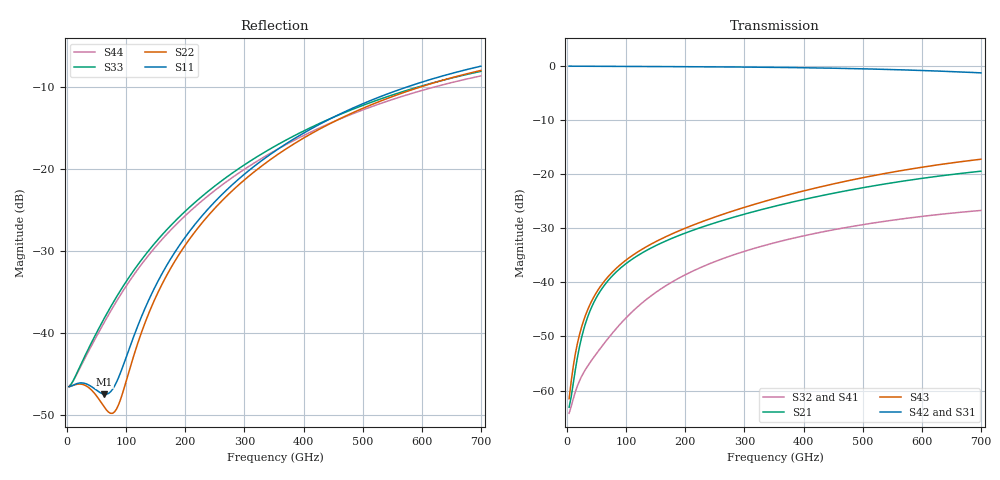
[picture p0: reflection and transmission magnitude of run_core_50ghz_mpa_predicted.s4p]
#  Hz  S  RI  R  50
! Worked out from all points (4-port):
!   200 points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, 3.5 GHz to 700 GHz, reference 50 ohm
!   strongest paths, dB at 3.5 GHz, 178.5 GHz, 353.5 GHz, 528.5 GHz, 700 GHz:
!     S42: 0.0, -0.1, -0.3, -0.6, -1.3
!     S31: 0.0, -0.1, -0.3, -0.6, -1.3
!     S43: -61.5, -31.0, -24.4, -20.1, -17.2
!     S21: -63.1, -31.8, -25.9, -22.0, -19.5
!     S32: -64.2, -39.9, -32.6, -28.9, -26.7
!     S41: -64.2, -40.0, -32.7, -28.9, -26.7
!   lowest |S11| = -47.5 dB at 63 GHz (marker M1), VSWR 1.01, Z = 50.2 - j0.359 ohm
!   |S11| at or under -10 dB: start of sweep to 576.9 GHz
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3.5e9  0.00468 -1.39e-05  0.000623 0.000322  0.9948 -0.00852  -0.000566 0.000226
       0.000623 0.000323  0.00469 2.23e-05  -0.000568 0.000223  0.9948 -0.00847
       0.9948 -0.00843  -0.00056 0.000256  0.0047 7.81e-05  0.000669 0.000508
       -0.000561 0.000253  0.9947 -0.00842  0.000668 0.00051  0.0047 0.000144
2.45e10  0.00488 -0.000778  0.000272 0.00306  0.9915 -0.0582  -0.000142 0.00115
         0.000275 0.00306  0.00483 -0.000397  -0.000147 0.00113  0.9916 -0.058
         0.9917 -0.0577  -0.000109 0.00134  0.00651 -0.000523  0.000516 0.00381
         -0.000113 0.00132  0.9916 -0.0577  0.000522 0.00381  0.00637 9.6e-05
6.3e10  0.00223 -0.00357  0.00259 0.00901  0.9803 -0.1457  -1.41e-05 0.00227
        0.0026 0.00901  0.00257 -0.0024  -3.16e-05 0.00223  0.9805 -0.1452
        0.9806 -0.1447  0.000104 0.00274  0.0113 -0.00466  0.000963 0.0102
        9.3e-05 0.00268  0.9805 -0.1447  0.00098 0.0102  0.0112 -0.00278
8.4e10  -0.000938 -0.00493  0.00502 0.0115  0.9713 -0.1927  -2.12e-05 0.00318
        0.00503 0.0115  -0.000191 -0.00343  -4.97e-05 0.00312  0.9714 -0.1922
        0.9715 -0.1915  0.00016 0.00378  0.0147 -0.00778  0.00145 0.0135
        0.000144 0.0037  0.9714 -0.1915  0.00147 0.0135  0.0147 -0.00526
1.82e11  -0.0306 -0.003  0.0204 0.0162  0.8989 -0.4037  0.00293 0.00868
         0.0205 0.0163  -0.0271 -0.00119  0.0028 0.00857  0.8998 -0.4024
         0.9 -0.4007  0.00355 0.00978  0.035 -0.0322  0.00409 0.0285
         0.0035 0.00963  0.8999 -0.4004  0.00416 0.0285  0.0355 -0.0271
2.905e11  -0.0809 0.0306  0.0401 0.00976  0.7628 -0.6104  0.0119 0.0117
          0.0401 0.00979  -0.0736 0.0304  0.0116 0.0116  0.7654 -0.6089
          0.7662 -0.606  0.0132 0.0131  0.0579 -0.0816  0.00856 0.0468
          0.0131 0.0129  0.7665 -0.6056  0.00871 0.0467  0.0589 -0.0732
7e11  -0.0132 0.4209  0.0463 -0.0957  -0.0629 -0.8566  0.0322 -0.0289
      0.0464 -0.0957  -0.00808 0.3966  0.0318 -0.028  -0.0579 -0.8637
      -0.0518 -0.8602  0.0357 -0.0293  -0.0951 -0.3799  0.0873 0.1069
      0.0352 -0.0296  -0.0508 -0.8613  0.0872 0.106  -0.0801 -0.3585
